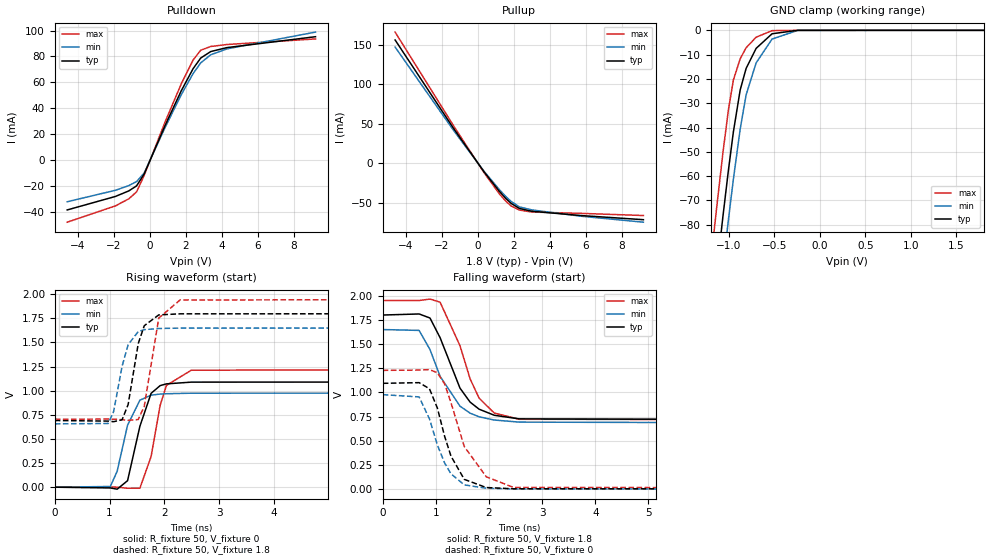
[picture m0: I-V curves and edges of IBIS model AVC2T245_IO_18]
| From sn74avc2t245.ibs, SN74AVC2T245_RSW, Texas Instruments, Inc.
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[Model]   AVC2T245_IO_18
Model_type  I/O
Vinl=0.5775
Vinh=1.2675
Enable   Active-Low
Vref =   0
Rref =   2000
Cref =   15p
Vmeas =   0.9
| variable   typ   min   max
C_comp   4.92pF   4.31pF   5.59pF
| C_pullup   4.26pF   3.15pF   6.11pF
| C_pulldown   4.14pF   3.80pF   4.44pF
| C_tri-state   4.92pF   4.31pF   5.59pF
[Temperature Range]   40   100   -40
| Ambient temperature   25   85   -40
[Voltage range]   1.8   1.65   1.95
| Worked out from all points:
|   slope of the pulldown table from 0 to 0.27 V, typ, clamps not added: 30.8 ohm
|   slope of the pullup table from 0 to 0.27 V, typ, clamps not added: 31.5 ohm
|   GND clamp passes 1 mA (typ) near -0.50 V on its own axis
|   rising waveform, R_fixture 50, V_fixture 0: 20-80 % time 262ps typ, 260ps min, 255ps max; typ from 0 V to 1.09 V
|   falling waveform, R_fixture 50, V_fixture 1.8: 20-80 % time 552ps typ, 576ps min, 485ps max; typ from 1.8 V to 0.691 V
|   rising waveform, R_fixture 50, V_fixture 1.8: 20-80 % time 208ps typ, 220ps min, 202ps max; typ from 0.691 V to 1.8 V
|   falling waveform, R_fixture 50, V_fixture 0: 20-80 % time 376ps typ, 394ps min, 504ps max; typ from 1.09 V to 0 V
[GND Clamp]
| AVC2T245_IO_18
|   Voltage   I(typ)   I(min)   I(max)
-4.6V     -1.415A    -1.424A    -1.406A
-1.205V   -124mA     -145mA     -97.63mA
-1.135V   -99.98mA   -121mA     -73.45mA
-1.065V   -76.69mA   -97.53mA   -50.48mA
-1.005V   -57.74mA   -78.16mA   -32.82mA
-950mV    -41.82mA   -61.29mA   -20.43mA
-875mV    -24.5mA    -40.6mA    -11.7mA
-810mV    -15.67mA   -26.55mA   -7.164mA
-700mV    -7.419mA   -13.4mA    -2.83mA
-525mV    -1.409mA   -3.582mA   -123.7uA
-245mV    -1.787uA   -44.62uA   -2.46nA
1.8V      922.7pA    2.233uA    86.4pA
[Pulldown]
| AVC2T245_IO_18
|   Voltage   I(typ)   I(min)   I(max)
-4.6V     -38.2mA    -31.89mA   -47.63mA
-1.915V   -27.78mA   -23.04mA   -35.05mA
-1.175V   -23.51mA   -19.42mA   -29.61mA
-745mV    -19.67mA   -16.37mA   -24.31mA
-325mV    -10.6mA    -9.798mA   -11.7mA
845mV     26.99mA    25.43mA    29.72mA
1.74V     53.6mA     50.58mA    58.93mA
2.395V    70.57mA    66.78mA    77.22mA
2.82V     78.82mA    75.08mA    84.83mA
3.38V     83.82mA    81.33mA    87.73mA
4.27V     86.83mA    85.84mA    89.23mA
9.2V      95.24mA    98.8mA     93.53mA
[Pullup]
| AVC2T245_IO_18
|   Voltage   I(typ)   I(min)   I(max)
-4.6V     156.3mA    147.3mA    166.3mA
-1.335V   43.59mA    41.12mA    46.9mA
335mV     -10.62mA   -9.903mA   -11.7mA
1.205V    -35.95mA   -33.76mA   -39.12mA
1.555V    -44.69mA   -42.2mA    -48.17mA
1.85V     -50.93mA   -48.44mA   -54.16mA
2.31V     -57.32mA   -55.35mA   -59.33mA
2.995V    -60.83mA   -59.13mA   -61.87mA
5.71V     -66.25mA   -67.11mA   -63.49mA
9.2V      -71.55mA   -74.71mA   -66.26mA
[Ramp]
| AVC2T245_IO_18
| variable   typ   min   max
dV/dt_r   0.67/2.80E-10   0.60/2.72E-10   0.75/2.67E-10
dV/dt_f   0.67/5.58E-10   0.60/5.81E-10   0.76/4.98E-10
R_load = 50
[Rising Waveform]
| AVC2T245_IO_18
R_fixture =   50
C_fixture =   0
L_fixture =   0
V_fixture =   0
V_fixture_min = 0
V_fixture_max = 0
|   Time   V(typ)   V(min)   V(max)
0s        13.46nV    2.048uV    174.7pV
1.015ns   -7.825mV   7.345mV    1.712mV
1.14ns    -20.49mV   165.5mV    560.5uV
1.33ns    67.76mV    643.5mV    -10.85mV
1.555ns   631.7mV    901.7mV    -10.04mV
1.76ns    973mV      954.3mV    318mV
1.925ns   1.053V     965.2mV    848.6mV
2.04ns    1.071V     968.7mV    1.055V
2.495ns   1.089V     974.4mV    1.213V
28.38ns   1.094V     977.1mV    1.228V
[Falling Waveform]
| AVC2T245_IO_18
R_fixture =   50
C_fixture =   0
L_fixture =   0
V_fixture =   1.8
V_fixture_min = 1.65
V_fixture_max = 1.95
|   Time   V(typ)   V(min)   V(max)
0s        1.8V       1.65V      1.95V
685ps     1.811V     1.641V     1.95V
890ps     1.769V     1.443V     1.965V
1.08ns    1.566V     1.167V     1.933V
1.455ns   1.044V     857.8mV    1.482V
1.645ns   899.8mV    785.6mV    1.14V
1.815ns   826.5mV    747.8mV    939.9mV
2.1ns     763.8mV    714.7mV    786.7mV
2.57ns    726.6mV    693mV      722.3mV
28.38ns   691.1mV    656.5mV    704.9mV
[Rising Waveform]
| AVC2T245_IO_18
R_fixture =   50
C_fixture =   0
L_fixture =   0
V_fixture =   1.8
V_fixture_min = 1.65
V_fixture_max = 1.95
|   Time   V(typ)   V(min)   V(max)
0s        691.1mV    656.5mV    704.9mV
975ps     685.1mV    660.4mV    705.8mV
1.075ns   678.9mV    783.8mV    704.6mV
1.23ns    699mV      1.254V     699.7mV
1.34ns    856.6mV    1.477V     693.5mV
1.525ns   1.489V     1.613V     701.2mV
1.635ns   1.674V     1.633V     838.8mV
1.9ns     1.786V     1.645V     1.753V
2.29ns    1.797V     1.649V     1.941V
28.38ns   1.8V       1.65V      1.95V
[Falling Waveform]
| AVC2T245_IO_18
R_fixture =   50
C_fixture =   0
L_fixture =   0
V_fixture =   0
V_fixture_min = 0
V_fixture_max = 0
|   Time   V(typ)   V(min)   V(max)
0s        1.094V     977.1mV    1.228V
685ps     1.101V     953.7mV    1.231V
880ps     1.038V     726.3mV    1.236V
1.03ns    836.9mV    455.2mV    1.203V
1.165ns   546.9mV    271.5mV    1.088V
1.285ns   341.7mV    158.1mV    894.4mV
1.535ns   101.3mV    44.03mV    440.3mV
1.95ns    16.79mV    9.513mV    127.7mV
2.46ns    4.133mV    2.108mV    18.26mV
28.38ns   34nV       2.09uV     46.49nV
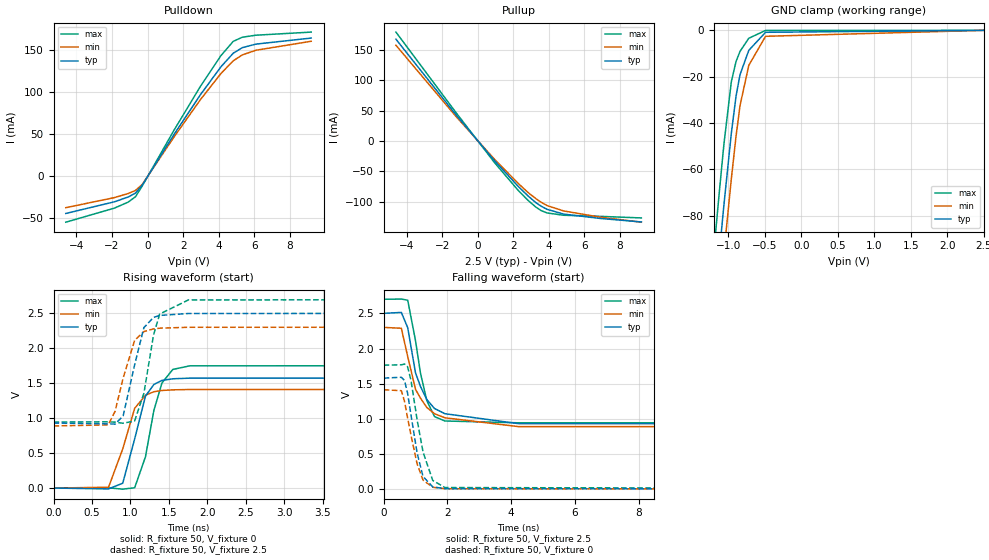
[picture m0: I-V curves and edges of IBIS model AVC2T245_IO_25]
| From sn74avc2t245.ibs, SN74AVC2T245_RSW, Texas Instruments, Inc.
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[Model]   AVC2T245_IO_25
Model_type  I/O
Vinl=0.7
Vinh=1.6
Enable   Active-Low
Vref =   0
Rref =   2000
Cref =   15p
Vmeas =   1.25
| variable   typ   min   max
C_comp   4.75pF   4.09pF   5.52pF
| C_pullup   3.76pF   2.91pF   4.84pF
| C_pulldown   3.88pF   3.47pF   4.35pF
| C_tri-state   4.75pF   4.09pF   5.52pF
[Temperature Range]   40   100   -40
| Ambient temperature   25   85   -40
[Voltage range]   2.5   2.3   2.7
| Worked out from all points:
|   slope of the pulldown table from 0 to 0.375 V, typ, clamps not added: 29.4 ohm
|   slope of the pullup table from 0 to 0.375 V, typ, clamps not added: 28.8 ohm
|   GND clamp passes 1 mA (typ) near -0.50 V on its own axis
|   rising waveform, R_fixture 50, V_fixture 0: 20-80 % time 194ps typ, 218ps min, 201ps max; typ from 0 V to 1.58 V
|   falling waveform, R_fixture 50, V_fixture 2.5: 20-80 % time 599ps typ, 629ps min, 408ps max; typ from 2.5 V to 0.929 V
|   rising waveform, R_fixture 50, V_fixture 2.5: 20-80 % time 167ps typ, 193ps min, 171ps max; typ from 0.929 V to 2.5 V
|   falling waveform, R_fixture 50, V_fixture 0: 20-80 % time 354ps typ, 390ps min, 429ps max; typ from 1.58 V to 0 V
[GND Clamp]
| AVC2T245_IO_25
|   Voltage   I(typ)   I(min)   I(max)
-4.6V     -1.415A    -1.424A    -1.406A
-1.225V   -131mA     -151.9mA   -104.7mA
-1.2V     -122.3mA   -143.2mA   -95.87mA
-1.13V    -98.28mA   -119.3mA   -71.76mA
-1.075V   -79.95mA   -100.8mA   -53.65mA
-1.06V    -75.06mA   -95.89mA   -48.92mA
-960mV    -44.57mA   -64.28mA   -22.28mA
-895mV    -28.42mA   -45.76mA   -13.44mA
-840mV    -19.08mA   -32.44mA   -9.076mA
-720mV    -8.634mA   -15.1mA    -3.417mA
-490mV    -845.1uA   -2.575mA   -44.26uA
2.5V      1.219nA    3.11uA     120.2pA
[Pulldown]
| AVC2T245_IO_25
|   Voltage   I(typ)   I(min)   I(max)
-4.6V     -44.06mA   -37.16mA   -54.4mA
-1.87V    -30.18mA   -25.2mA    -37.7mA
-1.095V   -24.49mA   -20.37mA   -30.58mA
-680mV    -19.82mA   -16.64mA   -24.14mA
-300mV    -10.24mA   -9.513mA   -11.28mA
1.515V    50.84mA    47.8mA     56mA
2.97V     97.07mA    91.22mA    107mA
4.125V    130.3mA    122.3mA    143.6mA
4.815V    146.4mA    137.4mA    160.5mA
5.325V    153mA      144.4mA    165.4mA
6.085V    157.2mA    149.9mA    167.8mA
9.2V      164.4mA    160.6mA    171.5mA
[Pullup]
| AVC2T245_IO_25
|   Voltage   I(typ)   I(min)   I(max)
-4.6V     167.2mA    157.3mA    178.9mA
-1.21V    42.52mA    39.86mA    46.1mA
950mV     -32.58mA   -30.29mA   -35.76mA
2.28V     -74.82mA   -69.9mA    -81.39mA
2.82V     -90.14mA   -84.49mA   -97.41mA
3.275V    -101.5mA   -94.98mA   -108.8mA
3.57V     -107.3mA   -100.8mA   -114.5mA
3.9V      -112.4mA   -106.2mA   -118.3mA
4.83V     -120.2mA   -115mA     -122.1mA
6.87V     -127.3mA   -125.2mA   -123.9mA
9.2V      -133.1mA   -133.5mA   -126.5mA
[Ramp]
| AVC2T245_IO_25
| variable   typ   min   max
dV/dt_r   0.96/2.05E-10   0.86/2.27E-10   1.07/2.12E-10
dV/dt_f   0.95/6.03E-10   0.85/6.37E-10   1.07/4.19E-10
R_load = 50
[Rising Waveform]
| AVC2T245_IO_25
R_fixture =   50
C_fixture =   0
L_fixture =   0
V_fixture =   0
V_fixture_min = 0
V_fixture_max = 0
|   Time   V(typ)   V(min)   V(max)
0s        17.75nV    2.703uV    235pV
715ps     -12.17mV   11.49mV    3.086mV
900ps     69.56mV    559.7mV    -15.94mV
1.055ns   702.5mV    1.139V     4.226mV
1.195ns   1.313V     1.326V     445.2mV
1.305ns   1.48V      1.376V     1.111V
1.41ns    1.538V     1.394V     1.502V
1.55ns    1.561V     1.403V     1.694V
1.77ns    1.57V      1.408V     1.746V
28.54ns   1.579V     1.414V     1.763V
[Falling Waveform]
| AVC2T245_IO_25
R_fixture =   50
C_fixture =   0
L_fixture =   0
V_fixture =   2.5
V_fixture_min = 2.3
V_fixture_max = 2.7
|   Time   V(typ)   V(min)   V(max)
0s        2.5V       2.3V       2.7V
555ps     2.513V     2.288V     2.703V
755ps     2.296V     1.885V     2.687V
1ns       1.652V     1.419V     2.11V
1.155ns   1.461V     1.294V     1.651V
1.355ns   1.273V     1.161V     1.258V
1.595ns   1.147V     1.073V     1.032V
1.92ns    1.073V     1.015V     969.3mV
4.235ns   931.3mV    889.1mV    943.5mV
28.54ns   929mV      887.7mV    943.4mV
[Rising Waveform]
| AVC2T245_IO_25
R_fixture =   50
C_fixture =   0
L_fixture =   0
V_fixture =   2.5
V_fixture_min = 2.3
V_fixture_max = 2.7
|   Time   V(typ)   V(min)   V(max)
0s        929mV      887.7mV    943.4mV
710ps     917.3mV    901.8mV    946mV
800ps     913.5mV    1.095V     941.4mV
905ps     1.031V     1.571V     926mV
1.055ns   1.763V     2.112V     958.6mV
1.175ns   2.292V     2.235V     1.355V
1.3ns     2.438V     2.274V     2.184V
1.38ns    2.466V     2.284V     2.486V
1.755ns   2.494V     2.297V     2.688V
28.54ns   2.5V       2.3V       2.7V
[Falling Waveform]
| AVC2T245_IO_25
R_fixture =   50
C_fixture =   0
L_fixture =   0
V_fixture =   0
V_fixture_min = 0
V_fixture_max = 0
|   Time   V(typ)   V(min)   V(max)
0s        1.579V     1.414V     1.763V
555ps     1.591V     1.4V       1.768V
655ps     1.545V     1.249V     1.779V
750ps     1.366V     1.016V     1.742V
860ps     1.047V     761.2mV    1.542V
1.05ns    513.5mV    358.9mV    986.3mV
1.235ns   180.8mV    128.8mV    529.8mV
1.54ns    32.32mV    27.37mV    123.3mV
1.925ns   7.365mV    6.435mV    22.83mV
28.54ns   62.36nV    2.769uV    172.9nV
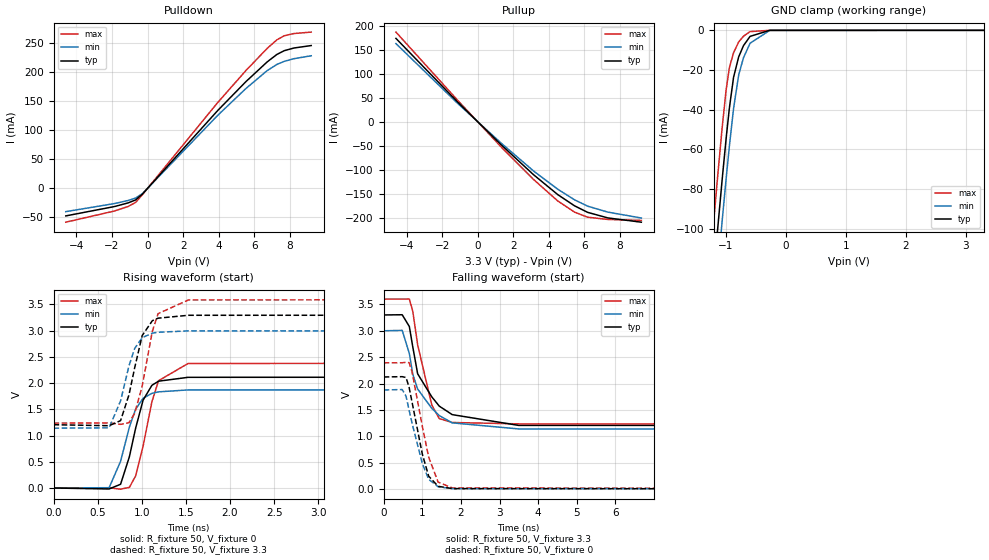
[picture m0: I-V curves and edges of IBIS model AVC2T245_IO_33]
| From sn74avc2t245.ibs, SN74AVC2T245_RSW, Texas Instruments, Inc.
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[Model]   AVC2T245_IO_33
Model_type  I/O
Vinl=0.8
Vinh=2.0
Enable   Active-Low
Vref =   0
Rref =   2000
Cref =   15p
Vmeas =   1.65
| variable   typ   min   max
C_comp   4.59pF   3.93pF   5.50pF
| C_pullup   3.52pF   2.74pF   4.57pF
| C_pulldown   3.72pF   3.28pF   4.31pF
| C_tri-state   4.59pF   3.93pF   5.50pF
[Temperature Range]   40   100   -40
| Ambient temperature   25   85   -40
[Voltage range]   3.3   3   3.6
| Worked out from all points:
|   slope of the pulldown table from 0 to 0.495 V, typ, clamps not added: 28.7 ohm
|   slope of the pullup table from 0 to 0.495 V, typ, clamps not added: 27.4 ohm
|   GND clamp passes 1 mA (typ) near -0.50 V on its own axis
|   rising waveform, R_fixture 50, V_fixture 0: 20-80 % time 187ps typ, 194ps min, 189ps max; typ from 0 V to 2.12 V
|   falling waveform, R_fixture 50, V_fixture 3.3: 20-80 % time 658ps typ, 618ps min, 389ps max; typ from 3.3 V to 1.21 V
|   rising waveform, R_fixture 50, V_fixture 3.3: 20-80 % time 168ps typ, 178ps min, 171ps max; typ from 1.21 V to 3.3 V
|   falling waveform, R_fixture 50, V_fixture 0: 20-80 % time 359ps typ, 393ps min, 405ps max; typ from 2.12 V to 0 V
[GND Clamp]
| AVC2T245_IO_33
|   Voltage   I(typ)   I(min)   I(max)
-4.6V     -1.415A    -1.424A    -1.406A
-1.205V   -124mA     -145mA     -97.63mA
-1.135V   -99.98mA   -121mA     -73.45mA
-1.06V    -75.06mA   -95.89mA   -48.92mA
-995mV    -54.72mA   -75.02mA   -30.21mA
-940mV    -39.15mA   -58.35mA   -18.79mA
-870mV    -23.62mA   -39.36mA   -11.3mA
-785mV    -13.39mA   -22.5mA    -5.847mA
-705mV    -7.712mA   -13.81mA   -2.972mA
-595mV    -3.051mA   -6.501mA   -650.4uA
-270mV    -3.886uA   -78.54uA   -7.595nA
3.3V      1.654nA    906.8nA    158.7pA
[Pulldown]
| AVC2T245_IO_33
|   Voltage   I(typ)   I(min)   I(max)
-4.6V     -47.8mA    -40.5mA    -58.64mA
-1.875V   -31.79mA   -26.64mA   -39.46mA
-1.095V   -25.4mA    -21.2mA    -31.57mA
-680mV    -20.38mA   -17.16mA   -24.75mA
-290mV    -10.14mA   -9.433mA   -11.16mA
3.935V    133.5mA    125.2mA    147.2mA
5.535V    183.7mA    171.8mA    202.8mA
6.725V    217.5mA    202.5mA    240.8mA
7.265V    230.2mA    213mA      255.4mA
7.675V    236.7mA    218.3mA    262.4mA
8.23V     241.4mA    223mA      266.3mA
9.2V      245.6mA    228mA      268.8mA
[Pullup]
| AVC2T245_IO_33
|   Voltage   I(typ)   I(min)   I(max)
-4.6V     174.2mA    163.4mA    187.3mA
-1.13V    41.52mA    38.75mA    45.15mA
1.37V     -49.43mA   -45.82mA   -54.19mA
3.13V     -109.7mA   -101.9mA   -119.6mA
4.5V      -151.4mA   -140.2mA   -164.7mA
5.44V     -174.7mA   -162.2mA   -187.9mA
6.18V     -188.4mA   -175.5mA   -198.5mA
7.315V    -200mA     -187.9mA   -203.2mA
9.2V      -208.9mA   -200.2mA   -205.2mA
[Ramp]
| AVC2T245_IO_33
| variable   typ   min   max
dV/dt_r   1.30/1.94E-10   1.14/1.98E-10   1.46/1.98E-10
dV/dt_f   1.26/6.66E-10   1.12/6.19E-10   1.43/3.91E-10
R_load = 50
[Rising Waveform]
| AVC2T245_IO_33
R_fixture =   50
C_fixture =   0
L_fixture =   0
V_fixture =   0
V_fixture_min = 0
V_fixture_max = 0
|   Time   V(typ)   V(min)   V(max)
0s        24.53nV    3.664uV    308.7pV
630ps     -18.23mV   5.886mV    4.205mV
760ps     71.76mV    508.4mV    -21.98mV
860ps     596.5mV    1.163V     12.73mV
930ps     1.136V     1.5V       228.3mV
1.015ns   1.674V     1.709V     796.7mV
1.115ns   1.957V     1.804V     1.643V
1.19ns    2.035V     1.832V     2.044V
1.525ns   2.109V     1.869V     2.373V
28.66ns   2.125V     1.879V     2.393V
[Falling Waveform]
| AVC2T245_IO_33
R_fixture =   50
C_fixture =   0
L_fixture =   0
V_fixture =   3.3
V_fixture_min = 3
V_fixture_max = 3.6
|   Time   V(typ)   V(min)   V(max)
0s        3.3V       3V         3.6V
480ps     3.304V     3.008V     3.6V
665ps     3.081V     2.569V     3.601V
755ps     2.692V     2.175V     3.366V
880ps     2.186V     1.897V     2.735V
1.245ns   1.75V      1.532V     1.597V
1.44ns    1.573V     1.394V     1.337V
1.775ns   1.412V     1.256V     1.263V
3.495ns   1.208V     1.141V     1.237V
28.66ns   1.206V     1.14V      1.236V
[Rising Waveform]
| AVC2T245_IO_33
R_fixture =   50
C_fixture =   0
L_fixture =   0
V_fixture =   3.3
V_fixture_min = 3
V_fixture_max = 3.6
|   Time   V(typ)   V(min)   V(max)
0s        1.206V     1.14V      1.236V
630ps     1.187V     1.147V     1.24V
760ps     1.284V     1.66V      1.213V
855ps     1.774V     2.327V     1.245V
920ps     2.292V     2.66V      1.423V
1.005ns   2.905V     2.864V     1.943V
1.12ns    3.188V     2.951V     2.986V
1.185ns   3.236V     2.967V     3.322V
1.53ns    3.291V     2.994V     3.584V
28.66ns   3.3V       3V         3.6V
[Falling Waveform]
| AVC2T245_IO_33
R_fixture =   50
C_fixture =   0
L_fixture =   0
V_fixture =   0
V_fixture_min = 0
V_fixture_max = 0
|   Time   V(typ)   V(min)   V(max)
0s        2.125V     1.879V     2.393V
480ps     2.131V     1.887V     2.394V
580ps     2.115V     1.761V     2.403V
660ps     1.926V     1.492V     2.396V
735ps     1.651V     1.251V     2.223V
1ns       668.2mV    488.4mV    1.195V
1.165ns   247mV      186.5mV    609mV
1.41ns    54.29mV    45.76mV    133.5mV
1.78ns    10.6mV     9.38mV     23.31mV
28.66ns   249nV      3.806uV    195nV
